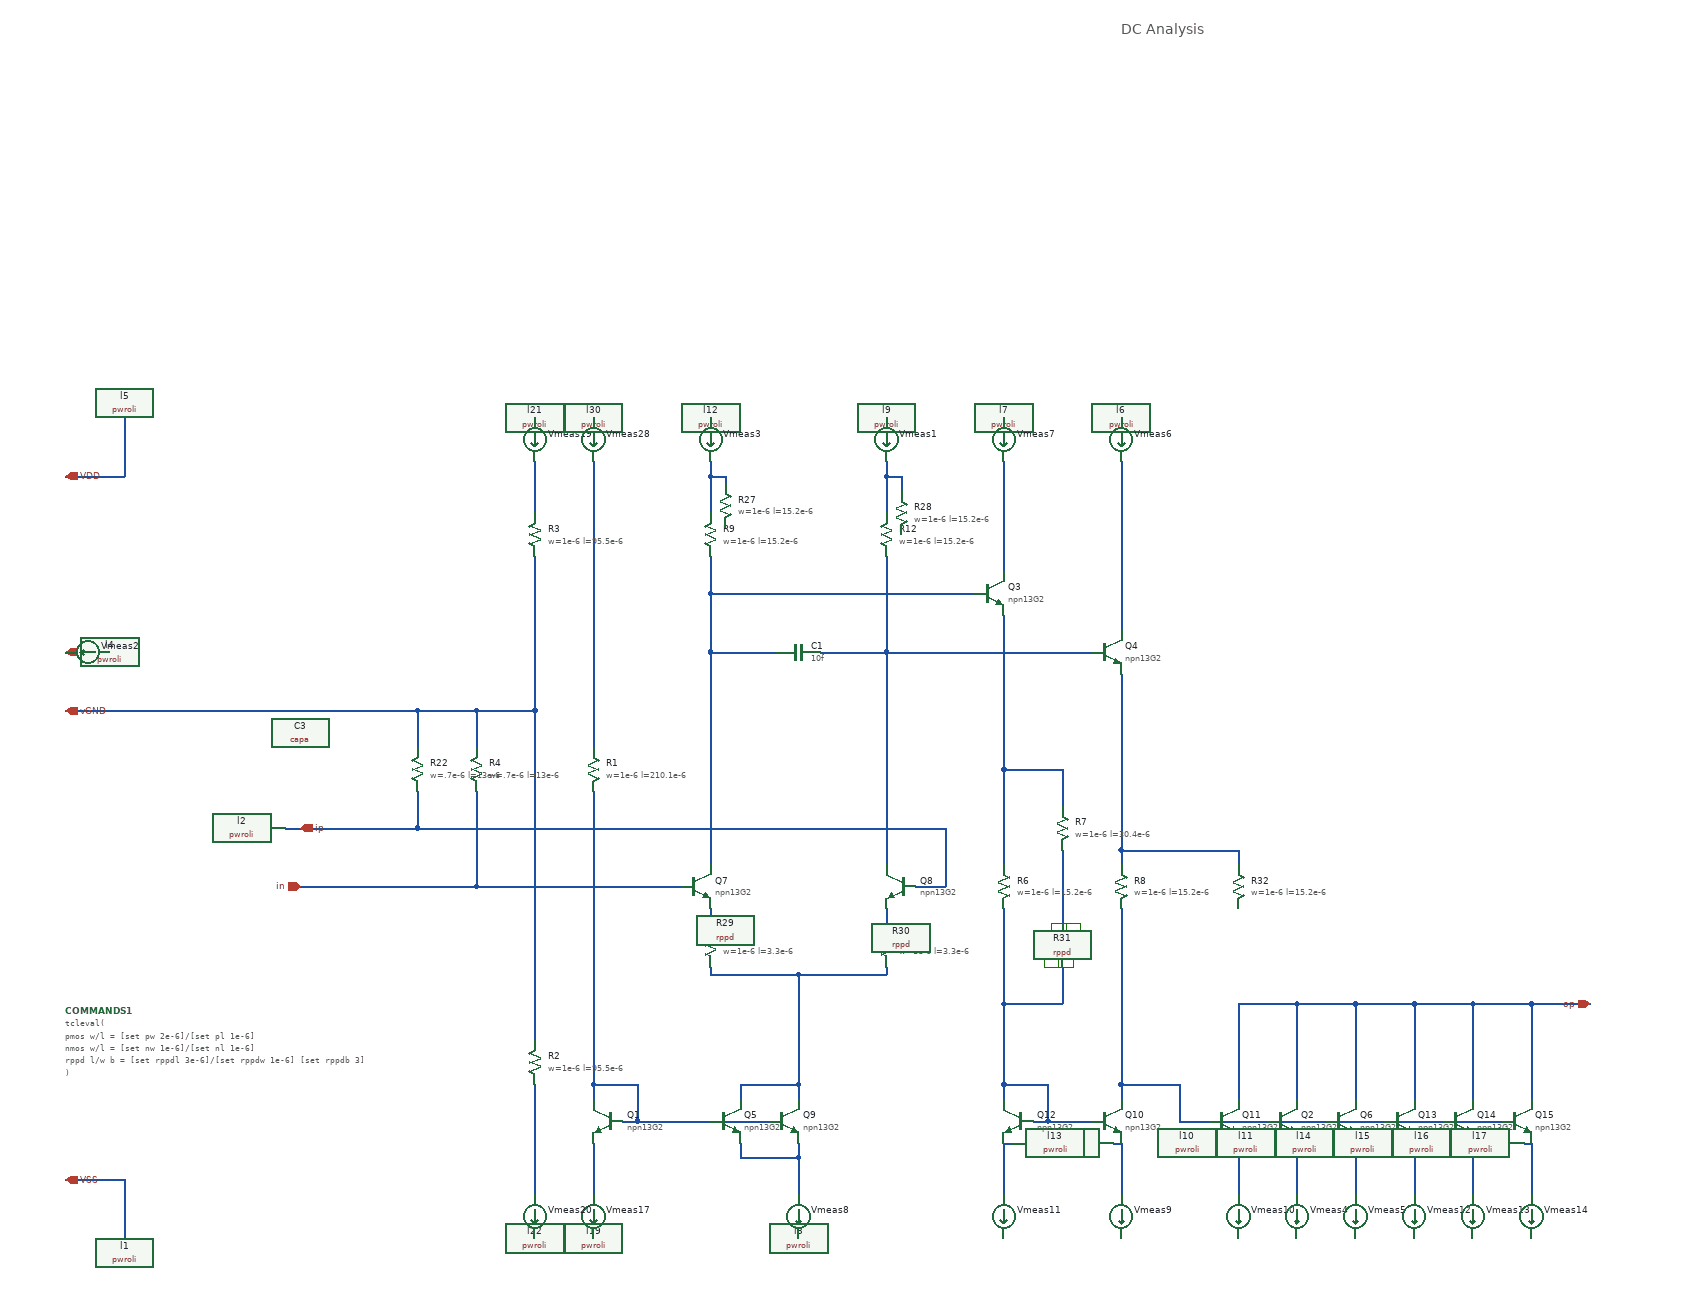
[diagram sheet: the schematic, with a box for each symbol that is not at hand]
v {xschem version=3.4.7RC file_version=1.2}
G {}
K {}
V {}
S {}
E {}
L 4 1985 -590 1985 -540 {}
L 4 2005 -590 2005 -540 {}
L 4 2025 -590 2025 -540 {}
L 4 2015 -580 2015 -530 {}
L 4 1995 -580 1995 -530 {}
L 4 1975 -580 1975 -530 {}
L 4 1975 -530 2015 -530 {}
L 4 1985 -590 2025 -590 {}
T {DC Analysis} 2080 -1820 0 0 0.6 0.6 { layer=2}
N 640 -240 720 -240 {
lab=VSS}
N 640 -1200 720 -1200 {
lab=VDD}
N 720 -240 720 -160 {
lab=VSS}
N 720 -1280 720 -1200 {
lab=VDD}
N 1360 -290 1360 -220 {lab=VSS}
N 1420 -370 1420 -320 {lab=#net1}
N 1360 -370 1420 -370 {lab=#net1}
N 1360 -370 1360 -350 {lab=#net1}
N 1120 -720 1840 -720 {lab=ip}
N 1280 -1220 1280 -1150 {lab=VDD}
N 1280 -370 1280 -220 {lab=VSS}
N 1120 -880 1120 -830 {lab=vGND}
N 1200 -880 1280 -880 {lab=vGND}
N 1120 -880 1200 -880 {lab=vGND}
N 1200 -880 1200 -830 {lab=vGND}
N 1200 -770 1200 -640 {lab=in}
N 1200 -640 1480 -640 {lab=in}
N 960 -640 1200 -640 {lab=in}
N 1840 -720 1840 -640 {lab=ip}
N 1800 -640 1840 -640 {lab=ip}
N 1120 -770 1120 -720 {lab=ip}
N 940 -720 1120 -720 {lab=ip}
N 1360 -770 1360 -370 {lab=#net1}
N 1520 -960 1610 -960 {lab=#net2}
N 1670 -960 1760 -960 {lab=#net3}
N 1520 -1200 1520 -1150 {lab=VDD}
N 1760 -1200 1760 -1150 {lab=VDD}
N 1360 -1220 1360 -830 {lab=VDD}
N 1560 -370 1640 -370 {lab=#net4}
N 1560 -270 1640 -270 {lab=VSS}
N 1920 -1220 1920 -1070 {lab=VDD}
N 1520 -1040 1880 -1040 {lab=#net2}
N 1520 -1090 1520 -1040 {lab=#net2}
N 2080 -290 2080 -220 {lab=VSS}
N 2070 -290 2080 -290 {lab=VSS}
N 2240 -290 2240 -220 {lab=VSS}
N 2230 -290 2240 -290 {lab=VSS}
N 1920 -290 1920 -220 {lab=VSS}
N 1920 -290 1930 -290 {lab=VSS}
N 1980 -320 2040 -320 {lab=#net5}
N 1980 -370 1980 -320 {lab=#net5}
N 1960 -320 1980 -320 {lab=#net5}
N 1920 -370 1980 -370 {lab=#net5}
N 2080 -370 2080 -350 {lab=#net6}
N 2080 -370 2160 -370 {lab=#net6}
N 2160 -370 2160 -320 {lab=#net6}
N 2160 -320 2600 -320 {lab=#net6}
N 1920 -370 1920 -350 {lab=#net5}
N 1760 -1090 1760 -960 {lab=#net3}
N 1760 -960 2040 -960 {lab=#net3}
N 2080 -1220 2080 -990 {lab=VDD}
N 1280 -1090 1280 -880 {lab=vGND}
N 1280 -880 1280 -430 {lab=vGND}
N 1520 -960 1520 -670 {lab=#net2}
N 1520 -1040 1520 -960 {lab=#net2}
N 1760 -960 1760 -670 {lab=#net3}
N 1520 -610 1520 -590 {lab=#net7}
N 1760 -610 1760 -590 {lab=#net8}
N 1520 -530 1520 -520 {lab=#net4}
N 1640 -520 1760 -520 {lab=#net4}
N 1760 -530 1760 -520 {lab=#net4}
N 1640 -520 1640 -370 {lab=#net4}
N 1520 -520 1640 -520 {lab=#net4}
N 1920 -480 1920 -370 {lab=#net5}
N 2080 -610 2080 -370 {lab=#net6}
N 1920 -800 1920 -670 {lab=#net9}
N 1420 -320 1600 -320 {lab=#net1}
N 1400 -320 1420 -320 {lab=#net1}
N 1920 -480 2000 -480 {lab=#net5}
N 1920 -610 1920 -480 {lab=#net5}
N 2000 -530 2000 -480 {lab=#net5}
N 2000 -690 2000 -590 {lab=#net10}
N 2000 -800 2000 -750 {lab=#net9}
N 1920 -800 2000 -800 {lab=#net9}
N 1560 -290 1560 -270 {lab=VSS}
N 1560 -370 1560 -350 {lab=#net4}
N 1640 -370 1640 -350 {lab=#net4}
N 1640 -270 1640 -220 {lab=VSS}
N 1640 -290 1640 -270 {lab=VSS}
N 640 -880 1120 -880 {lab=vGND}
N 2240 -480 2240 -350 {lab=op}
N 2640 -480 2720 -480 {lab=op}
N 1920 -1010 1920 -800 {lab=#net9}
N 2080 -690 2080 -670 {lab=#net11}
N 2320 -290 2320 -220 {lab=VSS}
N 2310 -290 2320 -290 {lab=VSS}
N 2400 -290 2400 -220 {lab=VSS}
N 2390 -290 2400 -290 {lab=VSS}
N 2480 -290 2480 -220 {lab=VSS}
N 2470 -290 2480 -290 {lab=VSS}
N 2560 -290 2560 -220 {lab=VSS}
N 2550 -290 2560 -290 {lab=VSS}
N 2640 -290 2640 -220 {lab=VSS}
N 2630 -290 2640 -290 {lab=VSS}
N 2320 -480 2320 -350 {lab=op}
N 2240 -480 2320 -480 {lab=op}
N 2400 -480 2400 -350 {lab=op}
N 2320 -480 2400 -480 {lab=op}
N 2480 -480 2480 -350 {lab=op}
N 2560 -480 2560 -350 {lab=op}
N 2400 -480 2480 -480 {lab=op}
N 2480 -480 2560 -480 {lab=op}
N 2640 -480 2640 -350 {lab=op}
N 2560 -480 2640 -480 {lab=op}
N 2240 -690 2240 -670 {lab=#net11}
N 2080 -690 2240 -690 {lab=#net11}
N 2080 -930 2080 -690 {lab=#net11}
N 1540 -1200 1540 -1190 {lab=VDD}
N 1520 -1200 1540 -1200 {lab=VDD}
N 1520 -1220 1520 -1200 {lab=VDD}
N 1780 -1200 1780 -1180 {lab=VDD}
N 1760 -1200 1780 -1200 {lab=VDD}
N 1760 -1220 1760 -1200 {lab=VDD}
C {ipin.sym} 960 -640 0 0 {name=p3 lab=in
}
C {iopin.sym} 640 -240 0 1 {name=p8 lab=VSS

}
C {pwroli.sym} 720 -160 0 0 {name=l1 lab=VSS}
C {iopin.sym} 640 -1200 0 1 {name=p9 lab=VDD}
C {pwroli.sym} 720 -1280 2 0 {name=l5 lab=VDD
}
C {pwroli.sym} 1640 -160 0 0 {name=l3 lab=VSS}
C {ammeter.sym} 1640 -190 0 0 {name=Vmeas8 savecurrent=true
lvs_ignore=short}
C {iopin.sym} 640 -960 0 1 {name=p13 lab=sink}
C {launcher.sym} 640 -720 0 0 {name=h1
descr="write LVS netlist"
tclcommand="
	xschem set netlist_type spice
	set lvs_ignore 1
	set lvs_netlist 1
	set spiceprefix 0
	set last_local_netlist_dir $local_netlist_dir
	set local_netlist_dir 0
	xschem netlist [xschem get current_name].cdl
	set local_netlist_dir $last_local_netlist_dir

"
}
C {ipin.sym} 960 -720 2 1 {name=p2 lab=ip
}
C {opin.sym} 2720 -480 2 1 {name=p5 lab=op

}
C {simulator_commands_shown.sym} 640 -470 0 0 {name=COMMANDS1
simulator=none
only_toplevel=true 

value="tcleval(

pmos w/l = [set pw 2e-6]/[set pl 1e-6]
nmos w/l = [set nw 1e-6]/[set nl 1e-6]

rppd l/w b = [set rppdl 3e-6]/[set rppdw 1e-6] [set rppdb 3]

)"}
C {launcher.sym} 640 -640 0 0 {name=h2
descr="load OP from TOP"
tclcommand="
	xschem annotate_op $\{netlist_dir\}/[file rootname [file tail [xschem get schname 0]]].raw 0;
	xschem raw_read $\{netlist_dir\}/[file rootname [file tail [xschem get schname 0]]]_dc.raw 0;

"
}
C {pwroli.sym} 1360 -160 0 1 {name=l19 lab=VSS}
C {ammeter.sym} 1360 -190 0 1 {name=Vmeas17 savecurrent=true
lvs_ignore=short}
C {pwroli.sym} 1520 -1280 2 1 {name=l12 lab=VDD
}
C {ammeter.sym} 1520 -1250 0 1 {name=Vmeas3 savecurrent=true
lvs_ignore=short}
C {pwroli.sym} 1280 -1280 2 1 {name=l21 lab=VDD
}
C {ammeter.sym} 1280 -1250 0 1 {name=Vmeas19 savecurrent=true
lvs_ignore=short}
C {pwroli.sym} 1280 -160 0 1 {name=l22 lab=VSS}
C {ammeter.sym} 1280 -190 0 1 {name=Vmeas20 savecurrent=true
lvs_ignore=short}
C {capa.sym} 1640 -960 1 0 {name=C1
m=1
value=10f
footprint=1206
device="ceramic capacitor"
spice_ignore=true
}
C {npn13G2oli.sym} 1500 -640 0 0 {name=Q7
model=npn13G2
spiceprefix=X
Nx=1
le=900e-9
Sub=VSS}
C {npn13G2oli.sym} 1780 -640 0 1 {name=Q8
model=npn13G2
spiceprefix=X
Nx=1
le=900e-9
Sub=VSS}
C {pwroli.sym} 1760 -1280 2 1 {name=l9 lab=VDD
}
C {ammeter.sym} 1760 -1250 0 1 {name=Vmeas1 savecurrent=true
lvs_ignore=short}
C {launcher.sym} 1680 -1680 0 0 {name=h3
descr="write LVS netlist"
tclcommand="
	xschem set netlist_type spice
	set lvs_ignore 1
	set lvs_netlist 1
	set spiceprefix 0
	set last_local_netlist_dir $local_netlist_dir
	set local_netlist_dir 0
	xschem netlist [xschem get current_name].cdl
	set local_netlist_dir $last_local_netlist_dir

"
}
C {pwroli.sym} 1360 -1280 2 1 {name=l30 lab=VDD
}
C {ammeter.sym} 1360 -1250 0 1 {name=Vmeas28 savecurrent=true
lvs_ignore=short}
C {npn13G2oli.sym} 1620 -320 0 0 {name=Q9
model=npn13G2
spiceprefix=X
Nx=1
le=900e-9
Sub=VSS}
C {npn13G2oli.sym} 1540 -320 0 0 {name=Q5
model=npn13G2
spiceprefix=X
Nx=1
le=900e-9
Sub=VSS}
C {npn13G2oli.sym} 1900 -1040 0 0 {name=Q3
model=npn13G2
spiceprefix=X
Nx=1
le=900e-9
Sub=VSS}
C {npn13G2oli.sym} 2060 -960 0 0 {name=Q4
model=npn13G2
spiceprefix=X
Nx=1
le=900e-9
Sub=VSS}
C {pwroli.sym} 2080 -1280 2 1 {name=l6 lab=VDD
}
C {ammeter.sym} 2080 -1250 0 1 {name=Vmeas6 savecurrent=true
lvs_ignore=short}
C {pwroli.sym} 1920 -1280 2 1 {name=l7 lab=VDD
}
C {ammeter.sym} 1920 -1250 0 1 {name=Vmeas7 savecurrent=true
lvs_ignore=short}
C {pwroli.sym} 2080 -160 0 0 {name=l8 lab=VSS}
C {ammeter.sym} 2080 -190 0 0 {name=Vmeas9 savecurrent=true
lvs_ignore=short}
C {npn13G2oli.sym} 2060 -320 0 0 {name=Q10
model=npn13G2
spiceprefix=X
Nx=1
le=900e-9
Sub=VSS}
C {pwroli.sym} 2240 -160 0 0 {name=l10 lab=VSS}
C {ammeter.sym} 2240 -190 0 0 {name=Vmeas10 savecurrent=true
lvs_ignore=short}
C {npn13G2oli.sym} 2220 -320 0 0 {name=Q11
model=npn13G2
spiceprefix=X
Nx=1
le=900e-9
Sub=VSS}
C {pwroli.sym} 1920 -160 0 1 {name=l13 lab=VSS}
C {ammeter.sym} 1920 -190 0 1 {name=Vmeas11 savecurrent=true
lvs_ignore=short}
C {npn13G2oli.sym} 1940 -320 0 1 {name=Q12
model=npn13G2
spiceprefix=X
Nx=1
le=900e-9
Sub=VSS}
C {npn13G2oli.sym} 1380 -320 0 1 {name=Q1
model=npn13G2
spiceprefix=X
Nx=1
le=900e-9
Sub=VSS}
C {iopin.sym} 640 -880 0 1 {name=p1 lab=vGND}
C {capa.sym} 960 -850 0 0 {name=C3
m=1
value=1
footprint=1206
device="ceramic capacitor"
spice_ignore=true}
C {pwroli.sym} 960 -820 0 1 {name=l2 lab=VSS
spice_ignore=true}
C {pwroli.sym} 700 -960 3 1 {name=l4 lab=VDD
}
C {ammeter.sym} 670 -960 1 1 {name=Vmeas2 savecurrent=true
lvs_ignore=flase
spice_ignore=short}
C {ngspice_probe.sym} 1280 -880 0 0 {name=r11
}
C {ngspice_probe.sym} 1640 -520 0 0 {name=r13
}
C {ngspice_probe.sym} 1520 -1040 0 0 {name=r14
}
C {ngspice_probe.sym} 1760 -960 0 0 {name=r16
}
C {ngspice_probe.sym} 1920 -370 0 0 {name=r17
}
C {ngspice_probe.sym} 2080 -370 0 0 {name=r18
}
C {ngspice_probe.sym} 2240 -380 0 0 {name=r19
}
C {ngspice_probe.sym} 1920 -800 0 0 {name=r20
}
C {ngspice_probe.sym} 2080 -800 0 0 {name=r21
}
C {launcher.sym} 1680 -1620 0 0 {name=h4
descr="xschem annotate_op"
tclcommand="
xschem raw_clear
xschem annotate_op $\{netlist_dir\}/$\{schematic\}_mos$\{mos_corner\}.spice.raw 0
"
}
C {launcher.sym} 1240 -1740 0 0 {
descr="xyce netlist simulate corners ALL" 

tclcommand="

    proc simulate_and_plot \{corners load_the_plots\} \{

	global netlist_dir
	global execute
	global mos_corner
	global sim_command
	global simulations

        set schematic [file rootname [file tail [xschem get schname 0]]]

        foreach corner $corners \{ 
            set mos_corner $\{corner\};
            foreach sim $simulations \{ 

                set sim_command $sim;

                if \{$\{sim\} == \{op\}\} \{
                    xschem netlist $\{netlist_dir\}/$\{schematic\}_mos$\{corner\}.spice
                \} else \{
                    xschem netlist $\{netlist_dir\}/$\{schematic\}_$\{sim\}_mos$\{corner\}.spice
                \}
            \}
        \}

        puts netlists_written;

        foreach corner $corners \{ 
            foreach sim $simulations \{

                if \{$\{sim\} == \{op\}\} \{
                    xschem set netlist_name $\{schematic\}_mos$\{corner\}.spice
                \} else \{
                    xschem set netlist_name $\{schematic\}_$\{sim\}_mos$\{corner\}.spice
                \}

                set id_$\{sim\}_$\{corner\} [simulate ]
            \}
        \}

        puts sims_started;

        while \{[llength [get_running_cmds]]\} \{

            puts -nonewline .; flush stdout;

            delay 99;
        \}

        if \{$\{load_the_plots\}\} \{
            xschem raw_clear;
            xschem annotate_op $\{netlist_dir\}/$\{schematic\}_mostt.spice.raw 0
        \}

        puts done

    \}


    xschem set netlist_type spice
    set lvs_ignore 0
    set lvs_netlist 0
    set spiceprefix 1

    simulate_and_plot $\{corners\} true
"
}
C {sg13g2_pr/rppd.sym} 1280 -400 2 0 {name=R2
w=1e-6
l=95.5e-6
model=rppd
spiceprefix=X
b=0
m=1
}
C {sg13g2_pr/rppd.sym} 1280 -1120 2 0 {name=R3
w=1e-6
l=95.5e-6
model=rppd
spiceprefix=X
b=0
m=1
}
C {sg13g2_pr/rppd.sym} 1120 -800 2 0 {name=R22
w=.7e-6
l=13e-6
model=rppd
spiceprefix=X
b=0
m=1
}
C {sg13g2_pr/rppd.sym} 1200 -800 2 0 {name=R4
w=.7e-6
l=13e-6
model=rppd
spiceprefix=X
b=0
m=1
}
C {sg13g2_pr/rppd.sym} 1520 -560 2 0 {name=R5
w=1e-6
l=3.3e-6
model=rppd
spiceprefix=X
b=0
m=3
}
C {sg13g2_pr/rppd.sym} 1760 -560 2 0 {name=R10
w=1e-6
l=3.3e-6
model=rppd
spiceprefix=X
b=0
m=3
}
C {sg13g2_pr/rppd.sym} 1520 -1120 2 0 {name=R9
w=1e-6
l=15.2e-6
model=rppd
spiceprefix=X
b=0
m=2
}
C {sg13g2_pr/rppd.sym} 1760 -1120 2 0 {name=R12
w=1e-6
l=15.2e-6
model=rppd
spiceprefix=X
b=0
m=2
}
C {sg13g2_pr/rppd.sym} 1920 -640 0 0 {name=R6
w=1e-6
l=15.2e-6
model=rppd
spiceprefix=X
b=0
m=1
}
C {sg13g2_pr/rppd.sym} 2080 -640 0 0 {name=R8
w=1e-6
l=15.2e-6
model=rppd
spiceprefix=X
b=0
m=1
}
C {sg13g2_pr/rppd.sym} 2000 -720 0 0 {name=R7
w=1e-6
l=30.4e-6
model=rppd
spiceprefix=X
b=0
m=1
}
C {pwroli.sym} 2320 -160 0 0 {name=l11 lab=VSS}
C {ammeter.sym} 2320 -190 0 0 {name=Vmeas4 savecurrent=true
lvs_ignore=short}
C {npn13G2oli.sym} 2300 -320 0 0 {name=Q2
model=npn13G2
spiceprefix=X
Nx=1
le=900e-9
Sub=VSS}
C {ngspice_probe.sym} 2320 -380 0 0 {name=r15
}
C {pwroli.sym} 2400 -160 0 0 {name=l14 lab=VSS}
C {ammeter.sym} 2400 -190 0 0 {name=Vmeas5 savecurrent=true
lvs_ignore=short}
C {npn13G2oli.sym} 2380 -320 0 0 {name=Q6
model=npn13G2
spiceprefix=X
Nx=1
le=900e-9
Sub=VSS}
C {ngspice_probe.sym} 2400 -380 0 0 {name=r23
}
C {pwroli.sym} 2480 -160 0 0 {name=l15 lab=VSS}
C {ammeter.sym} 2480 -190 0 0 {name=Vmeas12 savecurrent=true
lvs_ignore=short}
C {npn13G2oli.sym} 2460 -320 0 0 {name=Q13
model=npn13G2
spiceprefix=X
Nx=1
le=900e-9
Sub=VSS}
C {ngspice_probe.sym} 2480 -380 0 0 {name=r24
}
C {pwroli.sym} 2560 -160 0 0 {name=l16 lab=VSS}
C {ammeter.sym} 2560 -190 0 0 {name=Vmeas13 savecurrent=true
lvs_ignore=short}
C {npn13G2oli.sym} 2540 -320 0 0 {name=Q14
model=npn13G2
spiceprefix=X
Nx=1
le=900e-9
Sub=VSS}
C {ngspice_probe.sym} 2560 -380 0 0 {name=r25
}
C {pwroli.sym} 2640 -160 0 0 {name=l17 lab=VSS}
C {ammeter.sym} 2640 -190 0 0 {name=Vmeas14 savecurrent=true
lvs_ignore=short}
C {npn13G2oli.sym} 2620 -320 0 0 {name=Q15
model=npn13G2
spiceprefix=X
Nx=1
le=900e-9
Sub=VSS}
C {ngspice_probe.sym} 2640 -380 0 0 {name=r26
}
C {sg13g2_pr/rppd.sym} 1360 -800 0 0 {name=R1
w=1e-6
l=210.1e-6
model=rppd
spiceprefix=X
b=0
m=1
}
C {sg13g2_pr/rppd.sym} 1540 -1160 0 0 {name=R27
w=1e-6
l=15.2e-6
model=rppd
spiceprefix=X
b=0
m=1
}
C {sg13g2_pr/rppd.sym} 1780 -1150 0 0 {name=R28
w=1e-6
l=15.2e-6
model=rppd
spiceprefix=X
b=0
m=1
}
C {sg13g2_pr/rppd.sym} 1540 -580 0 0 {name=R29
w=1e-6
l=3.3e-6
model=rppd
spiceprefix=X
b=0
m=1
}
C {sg13g2_pr/rppd.sym} 1780 -570 0 0 {name=R30
w=1e-6
l=3.3e-6
model=rppd
spiceprefix=X
b=0
m=1
}
C {sg13g2_pr/rppd.sym} 1980 -740 2 0 {name=R31
w=1e-6
l=15.2e-6
model=rppd
spiceprefix=X
b=0
m=1
}
C {sg13g2_pr/rppd.sym} 2240 -640 0 0 {name=R32
w=1e-6
l=15.2e-6
model=rppd
spiceprefix=X
b=0
m=1
}
